VERSION 5.7 ;
  NOWIREEXTENSIONATPIN ON ;
  DIVIDERCHAR "/" ;
  BUSBITCHARS "[]" ;
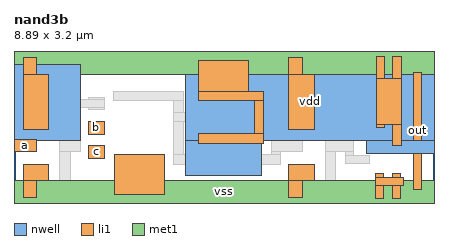
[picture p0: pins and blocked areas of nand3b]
MACRO nand3b
  CLASS BLOCK ;
  FOREIGN nand3b ;
  ORIGIN -0.010 0.000 ;
  SIZE 8.890 BY 3.200 ;
  PIN vdd
    DIRECTION INOUT ;
    USE POWER ;
    PORT
      LAYER nwell ;
        RECT 0.010 1.320 1.420 2.940 ;
        RECT 3.630 1.320 8.900 2.980 ;
        RECT 3.630 0.590 5.250 1.320 ;
        RECT 7.480 1.050 8.900 1.320 ;
      LAYER li1 ;
        RECT 0.210 2.720 0.490 3.080 ;
        RECT 0.210 1.550 0.750 2.720 ;
        RECT 3.910 2.370 4.970 3.020 ;
        RECT 5.830 2.720 6.110 3.080 ;
        RECT 3.910 2.170 5.300 2.370 ;
        RECT 5.100 1.470 5.300 2.170 ;
        RECT 5.830 1.550 6.370 2.720 ;
        RECT 7.680 2.630 7.850 3.100 ;
        RECT 8.030 2.630 8.210 3.100 ;
        RECT 7.680 1.670 8.210 2.630 ;
        RECT 7.680 1.590 7.850 1.670 ;
        RECT 3.910 1.270 5.300 1.470 ;
        RECT 8.020 1.210 8.210 1.670 ;
      LAYER met1 ;
        RECT 0.010 2.720 8.900 3.200 ;
    END
  END vdd
  PIN a
    DIRECTION INPUT ;
    USE SIGNAL ;
    ANTENNAGATEAREA 0.252000 ;
    PORT
      LAYER li1 ;
        RECT 0.010 1.080 0.490 1.350 ;
    END
  END a
  PIN b
    DIRECTION INPUT ;
    USE SIGNAL ;
    ANTENNAGATEAREA 0.378000 ;
    PORT
      LAYER li1 ;
        RECT 1.590 1.460 1.920 1.730 ;
    END
  END b
  PIN c
    DIRECTION INPUT ;
    USE SIGNAL ;
    ANTENNAGATEAREA 0.378000 ;
    PORT
      LAYER li1 ;
        RECT 1.590 0.950 1.920 1.220 ;
    END
  END c
  PIN vss
    DIRECTION INOUT ;
    USE GROUND ;
    PORT
      LAYER li1 ;
        RECT 0.210 0.470 0.750 0.810 ;
        RECT 0.210 0.120 0.490 0.470 ;
        RECT 2.130 0.190 3.190 1.020 ;
        RECT 5.830 0.470 6.370 0.810 ;
        RECT 7.670 0.540 7.840 0.620 ;
        RECT 8.030 0.540 8.200 0.620 ;
        RECT 5.830 0.120 6.110 0.470 ;
        RECT 7.670 0.370 8.260 0.540 ;
        RECT 7.670 0.090 7.840 0.370 ;
        RECT 8.030 0.090 8.200 0.370 ;
      LAYER met1 ;
        RECT 0.010 0.000 8.900 0.480 ;
    END
  END vss
  PIN out
    DIRECTION OUTPUT ;
    USE SIGNAL ;
    ANTENNADIFFAREA 0.644800 ;
    PORT
      LAYER li1 ;
        RECT 8.470 0.290 8.640 2.760 ;
    END
  END out
  OBS
      LAYER li1 ;
        RECT 0.980 2.190 1.200 2.720 ;
        RECT 1.590 2.190 1.920 2.240 ;
        RECT 0.980 2.020 1.920 2.190 ;
        RECT 2.120 2.170 3.600 2.370 ;
        RECT 0.980 1.350 1.200 2.020 ;
        RECT 1.590 1.970 1.920 2.020 ;
        RECT 3.380 1.920 3.600 2.170 ;
        RECT 3.380 1.720 4.930 1.920 ;
        RECT 0.980 1.080 1.420 1.350 ;
        RECT 0.980 0.480 1.200 1.080 ;
        RECT 3.380 1.020 3.600 1.720 ;
        RECT 6.600 1.350 6.820 2.720 ;
        RECT 5.470 1.080 6.110 1.350 ;
        RECT 6.600 1.080 7.200 1.350 ;
        RECT 5.470 1.020 5.660 1.080 ;
        RECT 3.380 0.820 5.660 1.020 ;
        RECT 6.600 0.480 6.820 1.080 ;
        RECT 7.030 1.000 7.200 1.080 ;
        RECT 7.030 0.830 7.530 1.000 ;
  END
END nand3b
END LIBRARY

